VERSION 5.7 ;
  NOWIREEXTENSIONATPIN ON ;
  DIVIDERCHAR "/" ;
  BUSBITCHARS "[]" ;
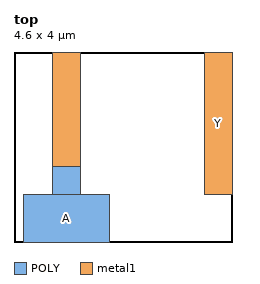
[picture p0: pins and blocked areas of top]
MACRO top
  CLASS BLOCK ;
  FOREIGN top ;
  ORIGIN 0.000 0.000 ;
  SIZE 4.600 BY 4.000 ;
  PIN A
    DIRECTION INPUT ;
    USE SIGNAL ;
    ANTENNAGATEAREA 0.400000 ;
    PORT
      LAYER POLY ;
        RECT 0.800 1.000 1.400 1.600 ;
        RECT 0.200 0.000 2.000 1.000 ;
      LAYER metal1 ;
        RECT 0.800 1.000 1.400 4.000 ;
    END
  END A
  PIN Y
    DIRECTION OUTPUT ;
    USE SIGNAL ;
    ANTENNADIFFAREA 0.600000 ;
    PORT
      LAYER metal1 ;
        RECT 4.000 1.000 4.600 4.000 ;
    END
  END Y
END top
END LIBRARY

